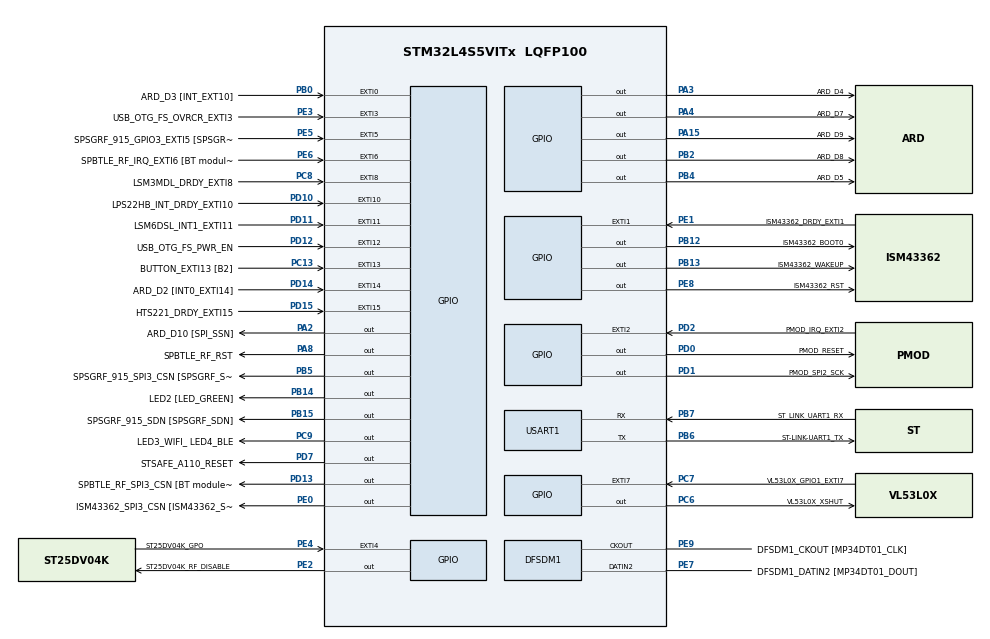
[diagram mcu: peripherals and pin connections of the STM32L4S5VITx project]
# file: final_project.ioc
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DFSDM1.Divider=40
DFSDM1.DmaMode_reg_FIL0=ENABLE
DFSDM1.FastMode_reg_FIL0=ENABLE
DFSDM1.Filter_regChannel_FIL0=DFSDM_CHANNEL_2
DFSDM1.Fosr_FIL0=250
DFSDM1.SincOrder_FIL0=DFSDM_FILTER_SINC3_ORDER
Dma.DFSDM1_FLT0.0.Direction=DMA_PERIPH_TO_MEMORY
Dma.DFSDM1_FLT0.0.EventEnable=DISABLE
Dma.DFSDM1_FLT0.0.Instance=DMA1_Channel4
Dma.DFSDM1_FLT0.0.MemDataAlignment=DMA_MDATAALIGN_WORD
Dma.DFSDM1_FLT0.0.MemInc=DMA_MINC_ENABLE
Dma.DFSDM1_FLT0.0.Mode=DMA_CIRCULAR
Dma.DFSDM1_FLT0.0.PeriphDataAlignment=DMA_PDATAALIGN_WORD
Dma.DFSDM1_FLT0.0.PeriphInc=DMA_PINC_DISABLE
Dma.DFSDM1_FLT0.0.Polarity=HAL_DMAMUX_REQUEST_GEN_RISING
Dma.DFSDM1_FLT0.0.Priority=DMA_PRIORITY_LOW
Dma.DFSDM1_FLT0.0.RequestNumber=1
Dma.DFSDM1_FLT0.0.SignalID=NONE
Dma.DFSDM1_FLT0.0.SyncEnable=DISABLE
Dma.DFSDM1_FLT0.0.SyncPolarity=HAL_DMAMUX_SYNC_NO_EVENT
Dma.DFSDM1_FLT0.0.SyncRequestNumber=1
Dma.DFSDM1_FLT0.0.SyncSignalID=NONE
Dma.Request0=DFSDM1_FLT0
Mcu.Family=STM32L4
Mcu.Name=STM32L4S5VITx
Mcu.Package=LQFP100
NVIC.DMA1_Channel4_IRQn=true\:0\:0\:false\:false\:true\:false\:true\:true
NVIC.EXTI15_10_IRQn=true\:0\:0\:false\:false\:true\:true\:true\:true
NVIC.EXTI9_5_IRQn=true\:0\:0\:false\:false\:true\:true\:true\:true
NVIC.PriorityGroup=NVIC_PRIORITYGROUP_4
PA0.GPIO_Label=ARD_D1 [UART4_TX]
PA0.GPIO_ModeDefaultPP=GPIO_MODE_AF_PP
PA0.GPIO_PuPd=GPIO_NOPULL
PA0.GPIO_Speed=GPIO_SPEED_FREQ_VERY_HIGH
PA0.Signal=UART4_TX
PA1.GPIO_Label=ARD_D0 [UART4_RX]
PA1.GPIO_ModeDefaultPP=GPIO_MODE_AF_PP
PA1.GPIO_PuPd=GPIO_NOPULL
PA1.GPIO_Speed=GPIO_SPEED_FREQ_VERY_HIGH
PA1.Signal=UART4_RX
PA13\ (JTMS/SWDIO).GPIO_Label=SYS_JTMS_SWDIO
PA13\ (JTMS/SWDIO).Signal=SYS_JTMS-SWDIO
PA14\ (JTCK/SWCLK).GPIO_Label=SYS_JTCK_SWCLK
PA14\ (JTCK/SWCLK).Signal=SYS_JTCK-SWCLK
PA15\ (JTDI).GPIO_Label=ARD_D9
PA15\ (JTDI).GPIO_ModeDefaultOutputPP=GPIO_MODE_OUTPUT_PP
PA15\ (JTDI).GPIO_PuPd=GPIO_NOPULL
PA15\ (JTDI).GPIO_Speed=GPIO_SPEED_FREQ_LOW
PA15\ (JTDI).PinState=GPIO_PIN_RESET
PA15\ (JTDI).Signal=GPIO_Output
PA2.GPIO_Label=ARD_D10 [SPI_SSN]
PA2.GPIO_ModeDefaultOutputPP=GPIO_MODE_OUTPUT_PP
PA2.GPIO_PuPd=GPIO_NOPULL
PA2.GPIO_Speed=GPIO_SPEED_FREQ_LOW
PA2.PinState=GPIO_PIN_RESET
PA2.Signal=GPIO_Output
PA3.GPIO_Label=ARD_D4
PA3.Signal=GPIO_Output
PA4.GPIO_Label=ARD_D7
PA4.Signal=GPIO_Output
PA5.GPIO_Label=ARD_D13 [SPI1_SCK/LED1]
PA5.GPIO_Mode=GPIO_MODE_AF_PP
PA5.GPIO_PuPd=GPIO_NOPULL
PA5.GPIO_Speed=GPIO_SPEED_FREQ_VERY_HIGH
PA5.Signal=SPI1_SCK
PA6.GPIO_Label=ARD_D12 [SPI1_MISO]
PA6.GPIO_Mode=GPIO_MODE_AF_PP
PA6.GPIO_PuPd=GPIO_NOPULL
PA6.GPIO_Speed=GPIO_SPEED_FREQ_VERY_HIGH
PA6.Signal=SPI1_MISO
PA7.GPIO_Label=ARD_D11 [SPI1_MOSI]
PA7.GPIO_Mode=GPIO_MODE_AF_PP
PA7.GPIO_PuPd=GPIO_NOPULL
PA7.GPIO_Speed=GPIO_SPEED_FREQ_VERY_HIGH
PA7.Signal=SPI1_MOSI
PA8.GPIO_Label=SPBTLE_RF_RST
PA8.GPIO_ModeDefaultOutputPP=GPIO_MODE_OUTPUT_PP
PA8.GPIO_PuPd=GPIO_NOPULL
PA8.GPIO_Speed=GPIO_SPEED_FREQ_LOW
PA8.PinState=GPIO_PIN_RESET
PA8.Signal=GPIO_Output
PA9.GPIO_Label=USB_OTG_FS_VBUS
PA9.GPIO_Mode=GPIO_MODE_INPUT
PA9.GPIO_PuPd=GPIO_NOPULL
PA9.Signal=USB_OTG_FS_VBUS
PB0.GPIO_Label=ARD_D3 [INT_EXT10]
PB0.GPIO_ModeDefaultEXTI=GPIO_MODE_IT_RISING
PB0.GPIO_PuPd=GPIO_NOPULL
PB0.Signal=GPXTI0
PB1.GPIO_Label=ARD_D6
PB1.GPIO_Speed=GPIO_SPEED_FREQ_LOW
PB1.Signal=S_TIM3_CH4
PB10.GPIO_Label=INTERNAL_I2C2_SCL [MEMs]
PB10.GPIO_Mode=GPIO_MODE_AF_OD
PB10.GPIO_PuPdOD=GPIO_PULLUP
PB10.GPIO_Speed=GPIO_SPEED_FREQ_VERY_HIGH
PB10.Signal=I2C2_SCL
PB11.GPIO_Label=INTERNAL_I2C2_SDA [MEMs]
PB11.GPIO_Mode=GPIO_MODE_AF_OD
PB11.GPIO_PuPdOD=GPIO_PULLUP
PB11.GPIO_Speed=GPIO_SPEED_FREQ_VERY_HIGH
PB11.Signal=I2C2_SDA
PB12.GPIO_Label=ISM43362_BOOT0
PB12.GPIO_ModeDefaultOutputPP=GPIO_MODE_OUTPUT_PP
PB12.GPIO_PuPd=GPIO_NOPULL
PB12.GPIO_Speed=GPIO_SPEED_FREQ_LOW
PB12.PinState=GPIO_PIN_RESET
PB12.Signal=GPIO_Output
PB13.GPIO_Label=ISM43362_WAKEUP
PB13.GPIO_ModeDefaultOutputPP=GPIO_MODE_OUTPUT_PP
PB13.GPIO_PuPd=GPIO_NOPULL
PB13.GPIO_Speed=GPIO_SPEED_FREQ_LOW
PB13.PinState=GPIO_PIN_RESET
PB13.Signal=GPIO_Output
PB14.GPIO_Label=LED2 [LED_GREEN]
PB14.GPIO_ModeDefaultOutputPP=GPIO_MODE_OUTPUT_PP
PB14.GPIO_PuPd=GPIO_NOPULL
PB14.GPIO_Speed=GPIO_SPEED_FREQ_LOW
PB14.PinState=GPIO_PIN_RESET
PB14.Signal=GPIO_Output
PB15.GPIO_Label=SPSGRF_915_SDN [SPSGRF_SDN]
PB15.Signal=GPIO_Output
PB2.GPIO_Label=ARD_D8
PB2.GPIO_ModeDefaultOutputPP=GPIO_MODE_OUTPUT_PP
PB2.GPIO_PuPd=GPIO_NOPULL
PB2.GPIO_Speed=GPIO_SPEED_FREQ_LOW
PB2.PinState=GPIO_PIN_RESET
PB2.Signal=GPIO_Output
PB3\ (JTDO/TRACESWO).GPIO_Label=SYS_JTD0_SWO
PB3\ (JTDO/TRACESWO).Signal=SYS_JTDO-SWO
PB4\ (NJTRST).GPIO_Label=ARD_D5
PB4\ (NJTRST).GPIO_ModeDefaultOutputPP=GPIO_MODE_OUTPUT_PP
PB4\ (NJTRST).GPIO_PuPd=GPIO_NOPULL
PB4\ (NJTRST).GPIO_Speed=GPIO_SPEED_FREQ_LOW
PB4\ (NJTRST).PinState=GPIO_PIN_RESET
PB4\ (NJTRST).Signal=GPIO_Output
PB5.GPIO_Label=SPSGRF_915_SPI3_CSN [SPSGRF_SPI_CS]
PB5.Signal=GPIO_Output
PB6.GPIO_FM6=__NULL
PB6.GPIO_Label=ST-LINK-UART1_TX
PB6.GPIO_ModeDefaultPP=GPIO_MODE_AF_PP
PB6.GPIO_PuPd=GPIO_NOPULL
PB6.GPIO_Speed=GPIO_SPEED_FREQ_VERY_HIGH
PB6.Mode=Asynchronous
PB6.Signal=USART1_TX
PB7.GPIO_FM7=__NULL
PB7.GPIO_Label=ST_LINK_UART1_RX
PB7.GPIO_ModeDefaultPP=GPIO_MODE_AF_PP
PB7.GPIO_PuPd=GPIO_NOPULL
PB7.GPIO_Speed=GPIO_SPEED_FREQ_VERY_HIGH
PB7.Mode=Asynchronous
PB7.Signal=USART1_RX
PB8.GPIO_FM8=__NULL
PB8.GPIO_Label=ARD_D15 [I2C1_SCL]
PB8.GPIO_Mode=GPIO_MODE_AF_OD
PB8.GPIO_PuPdOD=GPIO_PULLUP
PB8.GPIO_Speed=GPIO_SPEED_FREQ_VERY_HIGH
PB8.Signal=I2C1_SCL
PB9.GPIO_FM9=__NULL
PB9.GPIO_Label=ARD_D14 [I2C1_SDA]
PB9.GPIO_Mode=GPIO_MODE_AF_OD
PB9.GPIO_PuPdOD=GPIO_PULLUP
PB9.GPIO_Speed=GPIO_SPEED_FREQ_VERY_HIGH
PB9.Signal=I2C1_SDA
PC0.GPIO_Label=ARD_A5 [ADC]
PC0.GPIO_Mode=GPIO_MODE_ANALOG_ADC_CONTROL
PC0.GPIO_PuPd=GPIO_NOPULL
PC0.Signal=ADCx_IN1
PC1.GPIO_Label=ARD_A4 [ADC]
PC1.GPIO_Mode=GPIO_MODE_ANALOG_ADC_CONTROL
PC1.GPIO_PuPd=GPIO_NOPULL
PC1.Signal=ADCx_IN2
PC10.GPIO_Label=INTERNAL-SPI3_SCK [BT module_SPI_MOSI] [ISM43362_MOSI]
PC10.GPIO_Mode=GPIO_MODE_AF_PP
PC10.GPIO_PuPd=GPIO_NOPULL
PC10.GPIO_Speed=GPIO_SPEED_FREQ_VERY_HIGH
PC10.Signal=SPI3_SCK
PC11.GPIO_Label=INTERNAL_SPI3_MISO [BT module_SPI_MOSI] [ISM43362_MOSI]
PC11.GPIO_Mode=GPIO_MODE_AF_PP
PC11.GPIO_PuPd=GPIO_NOPULL
PC11.GPIO_Speed=GPIO_SPEED_FREQ_VERY_HIGH
PC11.Signal=SPI3_MISO
PC12.GPIO_Label=INTERNAL_SPI3_MOSI [BT module_SPI_MOSI] [ISM43362_MOSI]
PC12.GPIO_Mode=GPIO_MODE_AF_PP
PC12.GPIO_PuPd=GPIO_NOPULL
PC12.GPIO_Speed=GPIO_SPEED_FREQ_VERY_HIGH
PC12.Signal=SPI3_MOSI
PC13.GPIO_Label=BUTTON_EXTI13 [B2]
PC13.GPIO_ModeDefaultEXTI=GPIO_MODE_IT_RISING
PC13.GPIO_PuPd=GPIO_NOPULL
PC13.Signal=GPXTI13
PC2.GPIO_Label=ARD_A3 [ADC]
PC2.GPIO_Mode=GPIO_MODE_ANALOG_ADC_CONTROL
PC2.GPIO_PuPd=GPIO_NOPULL
PC2.Signal=ADCx_IN3
PC3.GPIO_Label=ARD_A2 [ADC]
PC3.GPIO_Mode=GPIO_MODE_ANALOG_ADC_CONTROL
PC3.GPIO_PuPd=GPIO_NOPULL
PC3.Signal=ADCx_IN4
PC4.GPIO_Label=ARD_A1 [ADC]
PC4.GPIO_Mode=GPIO_MODE_ANALOG_ADC_CONTROL
PC4.GPIO_PuPd=GPIO_NOPULL
PC4.Signal=ADCx_IN13
PC5.GPIO_Label=ARD_A0 [ADC]
PC5.GPIO_Mode=GPIO_MODE_ANALOG_ADC_CONTROL
PC5.GPIO_PuPd=GPIO_NOPULL
PC5.Signal=ADCx_IN14
PC6.GPIO_Label=VL53L0X_XSHUT
PC6.GPIO_ModeDefaultOutputPP=GPIO_MODE_OUTPUT_PP
PC6.GPIO_PuPd=GPIO_NOPULL
PC6.GPIO_Speed=GPIO_SPEED_FREQ_LOW
PC6.PinState=GPIO_PIN_RESET
PC6.Signal=GPIO_Output
PC7.GPIO_Label=VL53L0X_GPIO1_EXTI7
PC7.GPIO_ModeDefaultEXTI=GPIO_MODE_IT_RISING
PC7.GPIO_PuPd=GPIO_NOPULL
PC7.Signal=GPXTI7
PC8.GPIO_Label=LSM3MDL_DRDY_EXTI8
PC8.GPIO_ModeDefaultEXTI=GPIO_MODE_IT_RISING
PC8.GPIO_PuPd=GPIO_NOPULL
PC8.Signal=GPXTI8
PC9.GPIO_Label=LED3_WIFI_ LED4_BLE
PC9.GPIO_ModeDefaultOutputPP=GPIO_MODE_OUTPUT_PP
PC9.GPIO_PuPd=GPIO_NOPULL
PC9.GPIO_Speed=GPIO_SPEED_FREQ_LOW
PC9.PinState=GPIO_PIN_RESET
PC9.Signal=GPIO_Output
PD0.GPIO_Label=PMOD_RESET
PD0.GPIO_ModeDefaultOutputPP=GPIO_MODE_OUTPUT_PP
PD0.GPIO_PuPd=GPIO_NOPULL
PD0.GPIO_Speed=GPIO_SPEED_FREQ_LOW
PD0.PinState=GPIO_PIN_RESET
PD0.Signal=GPIO_Output
PD1.GPIO_Label=PMOD_SPI2_SCK
PD1.Signal=GPIO_Output
PD10.GPIO_Label=LPS22HB_INT_DRDY_EXTI10
PD10.GPIO_ModeDefaultEXTI=GPIO_MODE_IT_RISING
PD10.GPIO_PuPd=GPIO_NOPULL
PD10.Signal=GPXTI10
PD11.GPIO_Label=LSM6DSL_INT1_EXTI11
PD11.GPIO_ModeDefaultEXTI=GPIO_MODE_IT_RISING
PD11.GPIO_PuPd=GPIO_NOPULL
PD11.Signal=GPXTI11
PD12.GPIO_Label=USB_OTG_FS_PWR_EN
PD12.GPIO_ModeDefaultEXTI=GPIO_MODE_IT_RISING
PD12.GPIO_PuPd=GPIO_NOPULL
PD12.Signal=GPXTI12
PD13.GPIO_Label=SPBTLE_RF_SPI3_CSN [BT module_SPI_CS]
PD13.GPIO_ModeDefaultOutputPP=GPIO_MODE_OUTPUT_PP
PD13.GPIO_PuPd=GPIO_NOPULL
PD13.GPIO_Speed=GPIO_SPEED_FREQ_LOW
PD13.PinState=GPIO_PIN_RESET
PD13.Signal=GPIO_Output
PD14.GPIO_Label=ARD_D2 [INT0_EXTI14]
PD14.GPIO_ModeDefaultEXTI=GPIO_MODE_IT_RISING
PD14.GPIO_PuPd=GPIO_NOPULL
PD14.Signal=GPXTI14
PD15.GPIO_Label=HTS221_DRDY_EXTI15
PD15.GPIO_ModeDefaultEXTI=GPIO_MODE_IT_RISING
PD15.GPIO_PuPd=GPIO_NOPULL
PD15.Signal=GPXTI15
PD2.GPIO_Label=PMOD_IRQ_EXTI2
PD2.GPIO_ModeDefaultEXTI=GPIO_MODE_IT_RISING
PD2.GPIO_PuPd=GPIO_NOPULL
PD2.Signal=GPXTI2
PD3.GPIO_Label=PMOD_UART2_CTS
PD3.GPIO_Mode=GPIO_MODE_AF_PP
PD3.GPIO_PuPd=GPIO_NOPULL
PD3.GPIO_Speed=GPIO_SPEED_FREQ_VERY_HIGH
PD3.Signal=USART2_CTS
PD4.GPIO_Label=PMOD_UART2_RTS
PD4.GPIO_Mode=GPIO_MODE_AF_PP
PD4.GPIO_PuPd=GPIO_NOPULL
PD4.GPIO_Speed=GPIO_SPEED_FREQ_VERY_HIGH
PD4.Signal=USART2_RTS
PD5.GPIO_Label=PMOD_UART2_TX
PD5.GPIO_ModeDefaultPP=GPIO_MODE_AF_PP
PD5.GPIO_PuPd=GPIO_NOPULL
PD5.GPIO_Speed=GPIO_SPEED_FREQ_VERY_HIGH
PD5.Signal=USART2_TX
PD6.GPIO_Label=PMOD_UART2_RX
PD6.GPIO_ModeDefaultPP=GPIO_MODE_AF_PP
PD6.GPIO_PuPd=GPIO_NOPULL
PD6.GPIO_Speed=GPIO_SPEED_FREQ_VERY_HIGH
PD6.Signal=USART2_RX
PD7.GPIO_Label=STSAFE_A110_RESET
PD7.GPIO_ModeDefaultOutputPP=GPIO_MODE_OUTPUT_PP
PD7.GPIO_PuPd=GPIO_NOPULL
PD7.GPIO_Speed=GPIO_SPEED_FREQ_LOW
PD7.PinState=GPIO_PIN_RESET
PD7.Signal=GPIO_Output
PD8.GPIO_Label=INTERNAL_UART3_TX [ISM43362_RX]
PD8.GPIO_ModeDefaultPP=GPIO_MODE_AF_PP
PD8.GPIO_PuPd=GPIO_NOPULL
PD8.GPIO_Speed=GPIO_SPEED_FREQ_VERY_HIGH
PD8.Signal=USART3_TX
PD9.GPIO_Label=INTERNAL_UART3_RX [ISM43362_TX]
PD9.GPIO_ModeDefaultPP=GPIO_MODE_AF_PP
PD9.GPIO_PuPd=GPIO_NOPULL
PD9.GPIO_Speed=GPIO_SPEED_FREQ_VERY_HIGH
PD9.Signal=USART3_RX
PE0.GPIO_Label=ISM43362_SPI3_CSN [ISM43362_SSN]
PE0.GPIO_ModeDefaultOutputPP=GPIO_MODE_OUTPUT_PP
PE0.GPIO_PuPd=GPIO_NOPULL
PE0.GPIO_Speed=GPIO_SPEED_FREQ_LOW
PE0.PinState=GPIO_PIN_RESET
PE0.Signal=GPIO_Output
PE1.GPIO_Label=ISM43362_DRDY_EXTI1
PE1.GPIO_ModeDefaultEXTI=GPIO_MODE_IT_RISING
PE1.GPIO_PuPd=GPIO_NOPULL
PE1.Signal=GPXTI1
PE10.GPIO_Label=QUADSPI_CLK [MX25R6435F_SCLK]
PE10.GPIO_Mode=GPIO_MODE_AF_PP
PE10.GPIO_PuPd=GPIO_NOPULL
PE10.GPIO_Speed_High_Default=GPIO_SPEED_FREQ_VERY_HIGH
PE10.Signal=OCTOSPIM_P1_CLK
PE11.GPIO_Label=QUADSPI_NCS [MX25R6435F_SCLK]
PE11.GPIO_Mode=GPIO_MODE_AF_PP
PE11.GPIO_PuPd=GPIO_NOPULL
PE11.GPIO_Speed_High_Default=GPIO_SPEED_FREQ_VERY_HIGH
PE11.Signal=OCTOSPIM_P1_NCS
PE12.GPIO_Label=OQUADSPI_BK1_IO0 [MX25R6435F_IO0]
PE12.GPIO_Mode=GPIO_MODE_AF_PP
PE12.GPIO_PuPd=GPIO_NOPULL
PE12.GPIO_Speed_High_Default=GPIO_SPEED_FREQ_VERY_HIGH
PE12.Signal=OCTOSPIM_P1_IO0
PE13.GPIO_Label=QUADSPI_BK1_IO1 [MX25R6435F_IO1]
PE13.GPIO_Mode=GPIO_MODE_AF_PP
PE13.GPIO_PuPd=GPIO_NOPULL
PE13.GPIO_Speed_High_Default=GPIO_SPEED_FREQ_VERY_HIGH
PE13.Signal=OCTOSPIM_P1_IO1
PE14.GPIO_Label=QUAD_SPI_BK1_IO2 [MX25R6435F_IO2]
PE14.GPIO_Mode=GPIO_MODE_AF_PP
PE14.GPIO_PuPd=GPIO_NOPULL
PE14.GPIO_Speed_High_Default=GPIO_SPEED_FREQ_VERY_HIGH
PE14.Signal=OCTOSPIM_P1_IO2
PE15.GPIO_Label=QUAD_SPI_BK1_IO3 [MX25R6435F_IO3]
PE15.GPIO_Mode=GPIO_MODE_AF_PP
PE15.GPIO_PuPd=GPIO_NOPULL
PE15.GPIO_Speed_High_Default=GPIO_SPEED_FREQ_VERY_HIGH
PE15.Signal=OCTOSPIM_P1_IO3
PE2.GPIO_Label=ST25DV04K_RF_DISABLE
PE2.GPIO_ModeDefaultOutputPP=GPIO_MODE_OUTPUT_PP
PE2.GPIO_PuPd=GPIO_NOPULL
PE2.GPIO_Speed=GPIO_SPEED_FREQ_LOW
PE2.PinState=GPIO_PIN_RESET
PE2.Signal=GPIO_Output
PE3.GPIO_Label=USB_OTG_FS_OVRCR_EXTI3
PE3.GPIO_ModeDefaultEXTI=GPIO_MODE_IT_RISING
PE3.GPIO_PuPd=GPIO_NOPULL
PE3.Signal=GPXTI3
PE4.GPIO_Label=ST25DV04K_GPO
PE4.GPIO_ModeDefaultEXTI=GPIO_MODE_IT_RISING
PE4.GPIO_PuPd=GPIO_NOPULL
PE4.Signal=GPXTI4
PE5.GPIO_Label=SPSGRF_915_GPIO3_EXTI5 [SPSGRF_GPIO_3]
PE5.Signal=GPXTI5
PE6.GPIO_Label=SPBTLE_RF_IRQ_EXTI6 [BT module_SPI_IRQ]
PE6.GPIO_ModeDefaultEXTI=GPIO_MODE_IT_RISING
PE6.GPIO_PuPd=GPIO_NOPULL
PE6.Signal=GPXTI6
PE7.GPIO_Label=DFSDM1_DATIN2 [MP34DT01_DOUT]
PE7.GPIO_Mode=GPIO_MODE_AF_PP
PE7.GPIO_PuPd=GPIO_NOPULL
PE7.GPIO_Speed=GPIO_SPEED_FREQ_LOW
PE7.Signal=S_DATAIN2DFSDM1
PE8.GPIO_Label=ISM43362_RST
PE8.GPIO_ModeDefaultOutputPP=GPIO_MODE_OUTPUT_PP
PE8.GPIO_PuPd=GPIO_NOPULL
PE8.GPIO_Speed=GPIO_SPEED_FREQ_LOW
PE8.PinState=GPIO_PIN_RESET
PE8.Signal=GPIO_Output
PE9.GPIO_Label=DFSDM1_CKOUT [MP34DT01_CLK]
PE9.GPIO_Mode=GPIO_MODE_AF_PP
PE9.GPIO_PuPd=GPIO_NOPULL
PE9.GPIO_Speed=GPIO_SPEED_FREQ_LOW
PE9.Signal=S_CKOUTDFSDM1
ProjectManager.HeapSize=0x800
ProjectManager.StackSize=0x800
ProjectManager.TargetToolchain=STM32CubeIDE
RCC.ADCFreq_Value=48000000
RCC.AHBFreq_Value=120000000
RCC.APB1Freq_Value=120000000
RCC.APB1TimFreq_Value=120000000
RCC.APB2Freq_Value=120000000
RCC.APB2TimFreq_Value=120000000
RCC.CortexFreq_Value=120000000
RCC.HCLKFreq_Value=120000000
RCC.HSE_VALUE=8000000
RCC.HSI48_VALUE=48000000
RCC.HSI_VALUE=16000000
RCC.LSE_VALUE=32768
RCC.MSI_VALUE=4000000
RCC.PLLN=60
RCC.PLLR=2
RCC.PLLSAI1N=24
RCC.SYSCLKFreq_VALUE=120000000
RCC.SYSCLKSource=RCC_SYSCLKSOURCE_PLLCLK
RCC.USBFreq_Value=48000000
RCC.VCOOutputFreq_Value=240000000
SH.ADCx_IN1.0=ADC1_IN1
SH.ADCx_IN13.0=ADC1_IN13
SH.ADCx_IN14.0=ADC1_IN14
SH.ADCx_IN2.0=ADC1_IN2
SH.ADCx_IN3.0=ADC1_IN3
SH.ADCx_IN4.0=ADC1_IN4
SH.S_CKOUTDFSDM1.0=DFSDM1_CKOUT,PDM_SPI_input_from_ch2_and_internal_clock
SH.S_CKOUTDFSDM1.1=DFSDM1_CKOUT,CKOUT
SH.S_DATAIN2DFSDM1.0=DFSDM1_DATIN2,PDM_SPI_input_from_ch2_and_internal_clock
SH.S_TIM3_CH4.0=TIM3_CH4
STMicroelectronics.X-CUBE-AI.10.2.0.HeapSize=0x800
STMicroelectronics.X-CUBE-AI.10.2.0.LatestDirectoryUsed-1f8b5e1a2ea34a3a9f5167a8e617dd88e72de3b8e7a9603df451df20f446a52c=C\:\\Users\\bryan\\Downloads
STMicroelectronics.X-CUBE-AI.10.2.0.ModelActualCompression-1f8b5e1a2ea34a3a9f5167a8e617dd88e72de3b8e7a9603df451df20f446a52c=0.0
STMicroelectronics.X-CUBE-AI.10.2.0.ModelCompression-1f8b5e1a2ea34a3a9f5167a8e617dd88e72de3b8e7a9603df451df20f446a52c=None
STMicroelectronics.X-CUBE-AI.10.2.0.ModelFlashOccupation-1f8b5e1a2ea34a3a9f5167a8e617dd88e72de3b8e7a9603df451df20f446a52c=272540
STMicroelectronics.X-CUBE-AI.10.2.0.ModelHashList=1f8b5e1a2ea34a3a9f5167a8e617dd88e72de3b8e7a9603df451df20f446a52c
STMicroelectronics.X-CUBE-AI.10.2.0.ModelKind-1f8b5e1a2ea34a3a9f5167a8e617dd88e72de3b8e7a9603df451df20f446a52c=ONNX
STMicroelectronics.X-CUBE-AI.10.2.0.ModelMacc-1f8b5e1a2ea34a3a9f5167a8e617dd88e72de3b8e7a9603df451df20f446a52c=65664
STMicroelectronics.X-CUBE-AI.10.2.0.ModelName-1f8b5e1a2ea34a3a9f5167a8e617dd88e72de3b8e7a9603df451df20f446a52c=network
STMicroelectronics.X-CUBE-AI.10.2.0.ModelNameList=network
STMicroelectronics.X-CUBE-AI.10.2.0.ModelRamOccupation-1f8b5e1a2ea34a3a9f5167a8e617dd88e72de3b8e7a9603df451df20f446a52c=17940
STMicroelectronics.X-CUBE-AI.10.2.0.ModelStructureFile-1f8b5e1a2ea34a3a9f5167a8e617dd88e72de3b8e7a9603df451df20f446a52c=C\:\\Users\\bryan\\Downloads\\fft_mlp_4096_16_3.onnx
STMicroelectronics.X-CUBE-AI.10.2.0.ModelType-1f8b5e1a2ea34a3a9f5167a8e617dd88e72de3b8e7a9603df451df20f446a52c=STM32Cube.AI MCU runtime
STMicroelectronics.X-CUBE-AI.10.2.0.StackSize=0x800
STMicroelectronics.X-CUBE-AI.10.2.0.WorkingBufferStartAddrList=0xFFFFFFFF
STMicroelectronics.X-CUBE-AI.10.2.0.XAaCUBEAaAICcArtificialOoIntelligenceJjCore=true
STMicroelectronics.X-CUBE-AI.10.2.0.copyWeightToRam=false
STMicroelectronics.X-CUBE-AI.10.2.0.copyWeightToRam-1f8b5e1a2ea34a3a9f5167a8e617dd88e72de3b8e7a9603df451df20f446a52c=false
STMicroelectronics.X-CUBE-AI.10.2.0.customLayerConfigEnabled=false
STMicroelectronics.X-CUBE-AI.10.2.0.customLayerConfigEnabled-1f8b5e1a2ea34a3a9f5167a8e617dd88e72de3b8e7a9603df451df20f446a52c=false
STMicroelectronics.X-CUBE-AI.10.2.0.noOnnxIoTranspose=false
STMicroelectronics.X-CUBE-AI.10.2.0.noOnnxIoTranspose-1f8b5e1a2ea34a3a9f5167a8e617dd88e72de3b8e7a9603df451df20f446a52c=false
STMicroelectronics.X-CUBE-AI.10.2.0.useInputAllocation=true
STMicroelectronics.X-CUBE-AI.10.2.0.useInputAllocation-1f8b5e1a2ea34a3a9f5167a8e617dd88e72de3b8e7a9603df451df20f446a52c=true
STMicroelectronics.X-CUBE-AI.10.2.0.useOutputAllocation=true
STMicroelectronics.X-CUBE-AI.10.2.0.useOutputAllocation-1f8b5e1a2ea34a3a9f5167a8e617dd88e72de3b8e7a9603df451df20f446a52c=true
USART1.VirtualMode-Asynchronous=VM_ASYNC
VP_STMicroelectronics.X-CUBE-AI_VS_ArtificialOoIntelligenceJjXAaCUBEAaAI_10.2.0.Mode=ArtificialOoIntelligenceJjXAaCUBEAaAI
board=B-L4S5I-IOT01A

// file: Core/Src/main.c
/* USER CODE BEGIN Header */
/**
  ******************************************************************************
  * @file           : main.c
  * @brief          : Main program body
  ******************************************************************************
  */
/* USER CODE END Header */

#include "main.h"

/* USER CODE BEGIN Includes */
#include <stdio.h>
#include "arm_math.h"
#include "math.h"

#include "network.h"
#include "network_data.h"
#include "scaler_data.h"
/* USER CODE END Includes */

DFSDM_Filter_HandleTypeDef hdfsdm1_filter0;
DFSDM_Channel_HandleTypeDef hdfsdm1_channel2;
DMA_HandleTypeDef hdma_dfsdm1_flt0;
UART_HandleTypeDef huart1;

/* USER CODE BEGIN PV */
#define AUDIO_REC 1024

#define FFT_SIZE 512
#define FFT_BINS (FFT_SIZE / 2)
#define FS 16000

#define FRAME_QUEUE_LEN 16
#define MODEL_INPUT_SIZE (FFT_BINS * FRAME_QUEUE_LEN)

int32_t RecBuf[AUDIO_REC];
int32_t PlayBuf[AUDIO_REC];

uint8_t DmaRecHalfBuffCplt = 0;
uint8_t DmaRecBuffCplt = 0;

arm_rfft_fast_instance_f32 fft;

float32_t fft_input[FFT_SIZE];
float32_t fft_output[FFT_SIZE];
float32_t fft_mag[FFT_BINS];

float32_t fft_queue[FRAME_QUEUE_LEN][FFT_BINS];
float32_t model_input[MODEL_INPUT_SIZE];

uint8_t fft_queue_index = 0;
uint8_t fft_queue_count = 0;
uint32_t frame_counter = 0;

uint32_t led_off_tick = 0;
uint8_t led_active = 0;

int32_t TestBuf[FFT_SIZE];

/* Cube.AI variables */
AI_ALIGNED(4) static ai_u8 ai_activations[AI_NETWORK_DATA_ACTIVATIONS_SIZE];

AI_ALIGNED(4) static ai_float ai_input_data[AI_NETWORK_IN_1_SIZE];
AI_ALIGNED(4) static ai_float ai_output_data[AI_NETWORK_OUT_1_SIZE];

static ai_handle ai_network_handle = AI_HANDLE_NULL;
static ai_buffer *ai_input_buf = NULL;
static ai_buffer *ai_output_buf = NULL;
/* USER CODE END PV */

void SystemClock_Config(void);
static void MX_GPIO_Init(void);
static void MX_DMA_Init(void);
static void MX_DFSDM1_Init(void);
static void MX_USART1_UART_Init(void);

/* USER CODE BEGIN 0 */
int __io_putchar(int ch)
{
    HAL_UART_Transmit(&huart1, (uint8_t *)&ch, 1, 0xFFFF);
    return ch;
}

int _write(int file, char *ptr, int len)
{
    HAL_UART_Transmit(&huart1, (uint8_t *)ptr, len, HAL_MAX_DELAY);
    return len;
}

int _close(int file)
{
    return -1;
}

int _fstat(int file, void *st)
{
    return 0;
}

int _isatty(int file)
{
    return 1;
}

int _lseek(int file, int ptr, int dir)
{
    return 0;
}

int _read(int file, char *ptr, int len)
{
    return 0;
}

void AI_Init_Custom(void)
{
    ai_error err;

    const ai_handle activations[] = {
        ai_activations
    };

    err = ai_network_create_and_init(
        &ai_network_handle,
        activations,
        NULL
    );

    if (err.type != AI_ERROR_NONE)
    {
        printf("AI create/init failed: type=%d code=%d\r\n",
               err.type,
               err.code);
        Error_Handler();
    }

    ai_input_buf = ai_network_inputs_get(ai_network_handle, NULL);
    ai_output_buf = ai_network_outputs_get(ai_network_handle, NULL);

    if (ai_input_buf == NULL || ai_output_buf == NULL)
    {
        printf("AI buffer get failed\r\n");
        Error_Handler();
    }

    ai_input_buf[0].data = AI_HANDLE_PTR(ai_input_data);
    ai_output_buf[0].data = AI_HANDLE_PTR(ai_output_data);

    printf("AI init OK\r\n");
}

void PushFFTFrame(float32_t *mag)
{
    for (int i = 0; i < FFT_BINS; i++)
    {
        fft_queue[fft_queue_index][i] = mag[i];
    }

    fft_queue_index = (fft_queue_index + 1) % FRAME_QUEUE_LEN;

    if (fft_queue_count < FRAME_QUEUE_LEN)
    {
        fft_queue_count++;
    }

    frame_counter++;
}

void MakeModelInput(void)
{
    int out_idx = 0;
    int start = fft_queue_index;

    /*
     * Python CSV shape:
     *   256 rows x 16 columns
     *
     * Python reshape(-1) row-major order:
     *   row0_col0, row0_col1, ..., row0_col15,
     *   row1_col0, row1_col1, ...
     *
     * Here:
     *   row = FFT bin / frequency index k
     *   col = time frame index t
     */
    for (int k = 0; k < FFT_BINS; k++)
    {
        for (int t = 0; t < FRAME_QUEUE_LEN; t++)
        {
            int frame_idx = (start + t) % FRAME_QUEUE_LEN;
            model_input[out_idx++] = fft_queue[frame_idx][k];
        }
    }
}

void LED_All_Off(void)
{
    HAL_GPIO_WritePin(LED2_GPIO_Port,
                      LED2_Pin,
                      GPIO_PIN_RESET);

    HAL_GPIO_WritePin(LED3_WIFI__LED4_BLE_GPIO_Port,
                      LED3_WIFI__LED4_BLE_Pin,
                      GPIO_PIN_RESET);
}

void LED_ShowPrediction(int pred)
{
    /*
     * LED is locked while active.
     * During the 3-second indication window,
     * new predictions will NOT interrupt the current LED.
     */
    if (led_active)
    {
        return;
    }

    LED_All_Off();

    if (pred == 1)
    {
        HAL_GPIO_WritePin(LED2_GPIO_Port,
                          LED2_Pin,
                          GPIO_PIN_SET);

        led_off_tick = HAL_GetTick();
        led_active = 1;
    }
    else if (pred == 2)
    {
        HAL_GPIO_WritePin(LED3_WIFI__LED4_BLE_GPIO_Port,
                          LED3_WIFI__LED4_BLE_Pin,
                          GPIO_PIN_SET);

        led_off_tick = HAL_GetTick();
        led_active = 1;
    }
    else
    {
        /*
         * pred == 0:
         * keep all LEDs off.
         * No lock needed.
         */
        LED_All_Off();
        led_active = 0;
    }
}

void LED_Update(void)
{
    if (led_active)
    {
        if ((HAL_GetTick() - led_off_tick) >= 3000)
        {
            LED_All_Off();
            led_active = 0;
        }
    }
}

void RunClassifier(float32_t *input_4096)
{
    for (int i = 0; i < MODEL_INPUT_SIZE; i++)
    {
        float scale = scaler_scale[i];

        if (scale == 0.0f)
        {
            scale = 1.0f;
        }

        ai_input_data[i] =
            (input_4096[i] - scaler_mean[i]) / scale;
    }

    ai_i32 batch = ai_network_run(
        ai_network_handle,
        ai_input_buf,
        ai_output_buf
    );

    if (batch != 1)
    {
        ai_error err = ai_network_get_error(ai_network_handle);

        printf("AI run failed: type=%d code=%d\r\n",
               err.type,
               err.code);
        return;
    }

    int pred = 0;
    float max_prob = ai_output_data[0];

    for (int i = 1; i < AI_NETWORK_OUT_1_SIZE; i++)
    {
        if (ai_output_data[i] > max_prob)
        {
            max_prob = ai_output_data[i];
            pred = i;
        }
    }

    int prob_int = (int)(max_prob * 1000.0f);

    printf("Prediction=%d prob=%d.%03d outputs:",
           pred,
           prob_int / 1000,
           prob_int % 1000);

    for (int i = 0; i < AI_NETWORK_OUT_1_SIZE; i++)
    {
        int out_int = (int)(ai_output_data[i] * 1000.0f);

        printf(" [%d]=%d.%03d",
               i,
               out_int / 1000,
               out_int % 1000);
    }

    printf(" frame=%lu\r\n",
           (unsigned long)frame_counter);

    LED_ShowPrediction(pred);
}

void ProcessFFT(int32_t *input)
{
    float32_t mean = 0.0f;

    for (int i = 0; i < FFT_SIZE; i++)
    {
        mean += input[i];
    }

    mean /= FFT_SIZE;

    for (int i = 0; i < FFT_SIZE; i++)
    {
        fft_input[i] = (float32_t)input[i] - mean;
    }

    for (int i = 0; i < FFT_SIZE; i++)
    {
        float32_t w =
            0.5f - 0.5f * cosf(2.0f * 3.1415926f * i / (FFT_SIZE - 1));

        fft_input[i] *= w;
    }

    arm_rfft_fast_f32(&fft, fft_input, fft_output, 0);
    arm_cmplx_mag_f32(fft_output, fft_mag, FFT_BINS);

    PushFFTFrame(fft_mag);

    if (fft_queue_count == FRAME_QUEUE_LEN)
    {
        MakeModelInput();
        RunClassifier(model_input);
    }
    else
    {
        printf("Collecting FFT frames: %d/%d\r\n",
               fft_queue_count,
               FRAME_QUEUE_LEN);
    }
}
/* USER CODE END 0 */

int main(void)
{
  /* USER CODE BEGIN 1 */
  uint16_t i = 0;
  /* USER CODE END 1 */

  HAL_Init();
  SystemClock_Config();

  MX_GPIO_Init();
  MX_DMA_Init();
  MX_DFSDM1_Init();
  MX_USART1_UART_Init();

  /* USER CODE BEGIN 2 */
  printf("System start\r\n");

  LED_All_Off();

  /*
   * LED boot test:
   * LED2 on 0.5 sec, then LED3 on 0.5 sec.
   * If these do not light up, the issue is GPIO/LED polarity, not AI.
   */
  HAL_GPIO_WritePin(LED2_GPIO_Port, LED2_Pin, GPIO_PIN_SET);
  HAL_Delay(500);
  HAL_GPIO_WritePin(LED2_GPIO_Port, LED2_Pin, GPIO_PIN_RESET);

  HAL_GPIO_WritePin(LED3_WIFI__LED4_BLE_GPIO_Port,
                    LED3_WIFI__LED4_BLE_Pin,
                    GPIO_PIN_SET);
  HAL_Delay(500);
  HAL_GPIO_WritePin(LED3_WIFI__LED4_BLE_GPIO_Port,
                    LED3_WIFI__LED4_BLE_Pin,
                    GPIO_PIN_RESET);

  arm_rfft_fast_init_f32(&fft, FFT_SIZE);

  AI_Init_Custom();

  if (HAL_DFSDM_FilterRegularStart_DMA(&hdfsdm1_filter0,
                                       RecBuf,
                                       AUDIO_REC) != HAL_OK)
  {
      printf("DFSDM DMA start failed\r\n");
      Error_Handler();
  }

  printf("DFSDM DMA started\r\n");
  /* USER CODE END 2 */

  while (1)
  {
    LED_Update();

    if (DmaRecHalfBuffCplt == 1)
    {
        for (i = 0; i < FFT_SIZE; i++)
        {
            PlayBuf[i] = RecBuf[i] >> 8;
        }

        DmaRecHalfBuffCplt = 0;
        ProcessFFT(&PlayBuf[0]);
    }

    if (DmaRecBuffCplt == 1)
    {
        for (i = 0; i < FFT_SIZE; i++)
        {
            PlayBuf[i] = RecBuf[i + FFT_SIZE] >> 8;
        }

        DmaRecBuffCplt = 0;
        ProcessFFT(&PlayBuf[0]);
    }
  }
}

void SystemClock_Config(void)
{
  RCC_OscInitTypeDef RCC_OscInitStruct = {0};
  RCC_ClkInitTypeDef RCC_ClkInitStruct = {0};

  if (HAL_PWREx_ControlVoltageScaling(PWR_REGULATOR_VOLTAGE_SCALE1) != HAL_OK)
  {
    Error_Handler();
  }

  RCC_OscInitStruct.OscillatorType = RCC_OSCILLATORTYPE_MSI;
  RCC_OscInitStruct.MSIState = RCC_MSI_ON;
  RCC_OscInitStruct.MSICalibrationValue = 0;
  RCC_OscInitStruct.MSIClockRange = RCC_MSIRANGE_6;
  RCC_OscInitStruct.PLL.PLLState = RCC_PLL_ON;
  RCC_OscInitStruct.PLL.PLLSource = RCC_PLLSOURCE_MSI;
  RCC_OscInitStruct.PLL.PLLM = 1;
  RCC_OscInitStruct.PLL.PLLN = 40;
  RCC_OscInitStruct.PLL.PLLP = RCC_PLLP_DIV2;
  RCC_OscInitStruct.PLL.PLLQ = RCC_PLLQ_DIV2;
  RCC_OscInitStruct.PLL.PLLR = RCC_PLLR_DIV2;

  if (HAL_RCC_OscConfig(&RCC_OscInitStruct) != HAL_OK)
  {
    Error_Handler();
  }

  RCC_ClkInitStruct.ClockType = RCC_CLOCKTYPE_HCLK |
                                RCC_CLOCKTYPE_SYSCLK |
                                RCC_CLOCKTYPE_PCLK1 |
                                RCC_CLOCKTYPE_PCLK2;

  RCC_ClkInitStruct.SYSCLKSource = RCC_SYSCLKSOURCE_PLLCLK;
  RCC_ClkInitStruct.AHBCLKDivider = RCC_SYSCLK_DIV1;
  RCC_ClkInitStruct.APB1CLKDivider = RCC_HCLK_DIV1;
  RCC_ClkInitStruct.APB2CLKDivider = RCC_HCLK_DIV1;

  if (HAL_RCC_ClockConfig(&RCC_ClkInitStruct, FLASH_LATENCY_3) != HAL_OK)
  {
    Error_Handler();
  }
}

static void MX_DFSDM1_Init(void)
{
  hdfsdm1_filter0.Instance = DFSDM1_Filter0;
  hdfsdm1_filter0.Init.RegularParam.Trigger = DFSDM_FILTER_SW_TRIGGER;
  hdfsdm1_filter0.Init.RegularParam.FastMode = ENABLE;
  hdfsdm1_filter0.Init.RegularParam.DmaMode = ENABLE;
  hdfsdm1_filter0.Init.FilterParam.SincOrder = DFSDM_FILTER_SINC3_ORDER;
  hdfsdm1_filter0.Init.FilterParam.Oversampling = 250;
  hdfsdm1_filter0.Init.FilterParam.IntOversampling = 1;

  if (HAL_DFSDM_FilterInit(&hdfsdm1_filter0) != HAL_OK)
  {
    Error_Handler();
  }

  hdfsdm1_channel2.Instance = DFSDM1_Channel2;
  hdfsdm1_channel2.Init.OutputClock.Activation = ENABLE;
  hdfsdm1_channel2.Init.OutputClock.Selection = DFSDM_CHANNEL_OUTPUT_CLOCK_SYSTEM;
  hdfsdm1_channel2.Init.OutputClock.Divider = 40;
  hdfsdm1_channel2.Init.Input.Multiplexer = DFSDM_CHANNEL_EXTERNAL_INPUTS;
  hdfsdm1_channel2.Init.Input.DataPacking = DFSDM_CHANNEL_STANDARD_MODE;
  hdfsdm1_channel2.Init.Input.Pins = DFSDM_CHANNEL_SAME_CHANNEL_PINS;
  hdfsdm1_channel2.Init.SerialInterface.Type = DFSDM_CHANNEL_SPI_RISING;
  hdfsdm1_channel2.Init.SerialInterface.SpiClock = DFSDM_CHANNEL_SPI_CLOCK_INTERNAL;
  hdfsdm1_channel2.Init.Awd.FilterOrder = DFSDM_CHANNEL_FASTSINC_ORDER;
  hdfsdm1_channel2.Init.Awd.Oversampling = 1;
  hdfsdm1_channel2.Init.Offset = 0;
  hdfsdm1_channel2.Init.RightBitShift = 0x00;

  if (HAL_DFSDM_ChannelInit(&hdfsdm1_channel2) != HAL_OK)
  {
    Error_Handler();
  }

  if (HAL_DFSDM_FilterConfigRegChannel(&hdfsdm1_filter0,
                                       DFSDM_CHANNEL_2,
                                       DFSDM_CONTINUOUS_CONV_ON) != HAL_OK)
  {
    Error_Handler();
  }
}

static void MX_USART1_UART_Init(void)
{
  huart1.Instance = USART1;
  huart1.Init.BaudRate = 115200;
  huart1.Init.WordLength = UART_WORDLENGTH_8B;
  huart1.Init.StopBits = UART_STOPBITS_1;
  huart1.Init.Parity = UART_PARITY_NONE;
  huart1.Init.Mode = UART_MODE_TX_RX;
  huart1.Init.HwFlowCtl = UART_HWCONTROL_NONE;
  huart1.Init.OverSampling = UART_OVERSAMPLING_16;
  huart1.Init.OneBitSampling = UART_ONE_BIT_SAMPLE_DISABLE;
  huart1.Init.ClockPrescaler = UART_PRESCALER_DIV1;
  huart1.AdvancedInit.AdvFeatureInit = UART_ADVFEATURE_NO_INIT;

  if (HAL_UART_Init(&huart1) != HAL_OK)
  {
    Error_Handler();
  }

  if (HAL_UARTEx_SetTxFifoThreshold(&huart1,
                                    UART_TXFIFO_THRESHOLD_1_8) != HAL_OK)
  {
    Error_Handler();
  }

  if (HAL_UARTEx_SetRxFifoThreshold(&huart1,
                                    UART_RXFIFO_THRESHOLD_1_8) != HAL_OK)
  {
    Error_Handler();
  }

  if (HAL_UARTEx_DisableFifoMode(&huart1) != HAL_OK)
  {
    Error_Handler();
  }
}

static void MX_DMA_Init(void)
{
  __HAL_RCC_DMAMUX1_CLK_ENABLE();
  __HAL_RCC_DMA1_CLK_ENABLE();

  HAL_NVIC_SetPriority(DMA1_Channel4_IRQn, 0, 0);
  HAL_NVIC_EnableIRQ(DMA1_Channel4_IRQn);
}

static void MX_GPIO_Init(void)
{
  GPIO_InitTypeDef GPIO_InitStruct = {0};

  __HAL_RCC_GPIOE_CLK_ENABLE();
  __HAL_RCC_GPIOA_CLK_ENABLE();
  __HAL_RCC_GPIOB_CLK_ENABLE();
  __HAL_RCC_GPIOC_CLK_ENABLE();

  HAL_GPIO_WritePin(LED2_GPIO_Port,
                    LED2_Pin,
                    GPIO_PIN_RESET);

  HAL_GPIO_WritePin(LED3_WIFI__LED4_BLE_GPIO_Port,
                    LED3_WIFI__LED4_BLE_Pin,
                    GPIO_PIN_RESET);

  GPIO_InitStruct.Pin = LED2_Pin;
  GPIO_InitStruct.Mode = GPIO_MODE_OUTPUT_PP;
  GPIO_InitStruct.Pull = GPIO_NOPULL;
  GPIO_InitStruct.Speed = GPIO_SPEED_FREQ_LOW;
  HAL_GPIO_Init(LED2_GPIO_Port, &GPIO_InitStruct);

  GPIO_InitStruct.Pin = LED3_WIFI__LED4_BLE_Pin;
  GPIO_InitStruct.Mode = GPIO_MODE_OUTPUT_PP;
  GPIO_InitStruct.Pull = GPIO_NOPULL;
  GPIO_InitStruct.Speed = GPIO_SPEED_FREQ_LOW;
  HAL_GPIO_Init(LED3_WIFI__LED4_BLE_GPIO_Port, &GPIO_InitStruct);
}

void HAL_DFSDM_FilterRegConvHalfCpltCallback(
    DFSDM_Filter_HandleTypeDef *hdfsdm_filter)
{
    DmaRecHalfBuffCplt = 1;
}

void HAL_DFSDM_FilterRegConvCpltCallback(
    DFSDM_Filter_HandleTypeDef *hdfsdm_filter)
{
    DmaRecBuffCplt = 1;
}

void Error_Handler(void)
{
  __disable_irq();
  while (1)
  {
  }
}
